VERSION 5.8 ;
BUSBITCHARS "[]" ;
DIVIDERCHAR "/" ;
UNITS
    DATABASE MICRONS 1000 ;
END UNITS

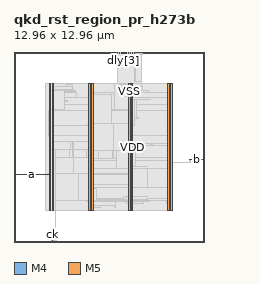
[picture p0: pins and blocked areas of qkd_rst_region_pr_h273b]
MACRO qkd_rst_region_pr_h273b
  FOREIGN qkd_rst_region_pr_h273b 0 0 ;
  CLASS BLOCK ;
  SIZE 12.96 BY 12.96 ;
  PIN a
    DIRECTION INPUT ;
    USE SIGNAL ;
    PORT
      LAYER M4 ;
        RECT  0 4.608 0.084 4.632 ;
    END
    PORT
      LAYER M4 ;
        RECT  0.06 4.608 2.408 4.632 ;
    END
  END a
  PIN b
    DIRECTION OUTPUT ;
    USE SIGNAL ;
    PORT
      LAYER M4 ;
        RECT  12.876 5.616 12.96 5.64 ;
    END
    PORT
      LAYER M4 ;
        RECT  11.977 5.616 12.924 5.64 ;
    END
  END b
  PIN ck
    DIRECTION INPUT ;
    USE SIGNAL ;
    PORT
      LAYER M5 ;
        RECT  2.592 0 2.616 0.084 ;
    END
    PORT
      LAYER M5 ;
        RECT  2.592 0.016 2.616 0.085 ;
    END
  END ck
  PIN dly[0]
    DIRECTION INPUT ;
    USE SIGNAL ;
    PORT
      LAYER M5 ;
        RECT  7.056 12.876 7.08 12.96 ;
    END
  END dly[0]
  PIN dly[1]
    DIRECTION INPUT ;
    USE SIGNAL ;
    PORT
      LAYER M5 ;
        RECT  7.2 12.876 7.224 12.96 ;
    END
  END dly[1]
  PIN dly[2]
    DIRECTION INPUT ;
    USE SIGNAL ;
    PORT
      LAYER M5 ;
        RECT  7.344 12.876 7.368 12.96 ;
    END
  END dly[2]
  PIN dly[3]
    DIRECTION INPUT ;
    USE SIGNAL ;
    PORT
      LAYER M5 ;
        RECT  7.488 12.876 7.512 12.96 ;
    END
  END dly[3]
  PIN dly[4]
    DIRECTION INPUT ;
    USE SIGNAL ;
    PORT
      LAYER M5 ;
        RECT  7.632 12.876 7.656 12.96 ;
    END
  END dly[4]
  PIN dly[5]
    DIRECTION INPUT ;
    USE SIGNAL ;
    PORT
      LAYER M5 ;
        RECT  7.776 12.876 7.8 12.96 ;
    END
  END dly[5]
  PIN dly[6]
    DIRECTION INPUT ;
    USE SIGNAL ;
    PORT
      LAYER M5 ;
        RECT  7.92 12.876 7.944 12.96 ;
    END
  END dly[6]
  PIN dly[7]
    DIRECTION INPUT ;
    USE SIGNAL ;
    PORT
      LAYER M5 ;
        RECT  8.064 12.876 8.088 12.96 ;
    END
  END dly[7]
  PIN por_n
    DIRECTION INPUT ;
    USE SIGNAL ;
    PORT
      LAYER M5 ;
        RECT  8.208 12.876 8.232 12.96 ;
    END
  END por_n
  PIN VDD
    DIRECTION INOUT ;
    USE POWER ;
    PORT
      LAYER M5 ;
        RECT  10.692 2.151 10.812 10.809 ;
        RECT  7.992 2.151 8.112 10.809 ;
        RECT  5.292 2.151 5.412 10.809 ;
        RECT  2.592 2.151 2.712 10.809 ;
    END
  END VDD
  PIN VSS
    DIRECTION INOUT ;
    USE GROUND ;
    PORT
      LAYER M5 ;
        RECT  10.5 2.137 10.62 10.823 ;
        RECT  7.8 2.137 7.92 10.823 ;
        RECT  5.1 2.137 5.22 10.823 ;
        RECT  2.4 2.137 2.52 10.823 ;
    END
  END VSS
  # OT_OBS_CLOSED layer=M5 d_um=1.536 added=5
  OBS
    LAYER RVTN ;
     RECT  2.16 2.16 10.8 2.295 ;
     RECT  2.16 2.565 10.8 2.835 ;
     RECT  2.16 3.105 10.8 3.375 ;
     RECT  2.16 3.645 10.8 3.915 ;
     RECT  2.16 4.185 10.8 4.455 ;
     RECT  2.16 4.725 10.8 4.995 ;
     RECT  2.16 5.265 10.8 5.535 ;
     RECT  2.16 5.805 10.8 6.075 ;
     RECT  2.16 6.345 10.8 6.615 ;
     RECT  2.16 6.885 10.8 7.155 ;
     RECT  2.16 7.425 10.8 7.695 ;
     RECT  2.16 7.965 10.8 8.235 ;
     RECT  2.16 8.505 10.8 8.775 ;
     RECT  2.16 9.045 10.8 9.315 ;
     RECT  2.16 9.585 10.8 9.855 ;
     RECT  2.16 10.125 10.8 10.395 ;
     RECT  2.16 10.665 10.8 10.8 ;
    LAYER RVTP ;
     RECT  2.16 2.295 10.8 2.565 ;
     RECT  2.16 2.835 10.8 3.105 ;
     RECT  2.16 3.375 10.8 3.645 ;
     RECT  2.16 3.915 10.8 4.185 ;
     RECT  2.16 4.455 10.8 4.725 ;
     RECT  2.16 4.995 10.8 5.265 ;
     RECT  2.16 5.535 10.8 5.805 ;
     RECT  2.16 6.075 10.8 6.345 ;
     RECT  2.16 6.615 10.8 6.885 ;
     RECT  2.16 7.155 10.8 7.425 ;
     RECT  2.16 7.695 10.8 7.965 ;
     RECT  2.16 8.235 10.8 8.505 ;
     RECT  2.16 8.775 10.8 9.045 ;
     RECT  2.16 9.315 10.8 9.585 ;
     RECT  2.16 9.855 10.8 10.125 ;
     RECT  2.16 10.395 10.8 10.665 ;
    LAYER M1 ;
     RECT  2.16 2.151 10.8 10.809 ;
    LAYER M2 ;
     RECT  2.16 2.151 10.8 10.809 ;
     RECT  10.8 2.421 10.812 10.539 ;
     RECT  10.812 5.436 12.011 5.454 ;
    LAYER M3 ;
     RECT  5.115 2.143 5.205 2.371 ;
     RECT  2.415 2.143 2.505 2.413 ;
     RECT  7.815 2.143 7.905 2.413 ;
     RECT  10.515 2.143 10.605 2.413 ;
     RECT  5.115 2.371 5.922 2.497 ;
     RECT  6.876 2.371 6.894 2.497 ;
     RECT  7.815 2.413 8.097 2.605 ;
     RECT  7.704 2.605 8.154 2.641 ;
     RECT  10.515 2.413 10.797 2.641 ;
     RECT  5.115 2.497 6.894 2.731 ;
     RECT  7.704 2.641 8.838 2.731 ;
     RECT  4.932 2.731 9.27 2.827 ;
     RECT  4.356 2.827 9.27 2.839 ;
     RECT  10.368 2.641 10.797 2.839 ;
     RECT  4.356 2.839 10.797 2.939 ;
     RECT  4.572 2.939 10.797 3.713 ;
     RECT  3.744 3.721 3.762 3.931 ;
     RECT  3.6 3.931 3.762 3.955 ;
     RECT  4.572 3.713 8.097 3.955 ;
     RECT  2.415 2.413 2.697 4.603 ;
     RECT  2.304 4.603 2.697 4.621 ;
     RECT  3.6 3.955 8.097 4.621 ;
     RECT  2.304 4.621 8.097 4.685 ;
     RECT  2.415 4.685 8.097 5.035 ;
     RECT  9.108 3.713 10.797 5.035 ;
     RECT  2.415 5.035 10.797 5.567 ;
     RECT  11.988 5.431 12.006 5.645 ;
     RECT  2.415 5.567 4.05 5.765 ;
     RECT  4.824 5.567 10.797 5.765 ;
     RECT  2.415 5.765 3.798 6.619 ;
     RECT  2.415 6.619 4.05 6.691 ;
     RECT  4.932 5.765 10.797 6.691 ;
     RECT  2.415 6.691 10.797 7.231 ;
     RECT  2.376 7.231 10.797 8.969 ;
     RECT  2.415 8.969 10.797 9.347 ;
     RECT  3.42 9.347 10.797 9.887 ;
     RECT  5.115 9.887 10.797 10.193 ;
     RECT  3.42 9.887 4.23 10.229 ;
     RECT  5.115 10.193 6.102 10.229 ;
     RECT  6.84 10.193 10.797 10.229 ;
     RECT  2.415 9.347 2.697 10.267 ;
     RECT  3.42 10.229 4.194 10.267 ;
     RECT  2.415 10.267 4.194 10.319 ;
     RECT  6.84 10.229 9.198 10.319 ;
     RECT  2.415 10.319 4.086 10.391 ;
     RECT  5.115 10.229 5.397 10.547 ;
     RECT  10.515 10.229 10.797 10.547 ;
     RECT  2.415 10.391 3.978 10.589 ;
     RECT  6.84 10.319 8.766 10.589 ;
     RECT  3.564 10.589 3.978 10.769 ;
     RECT  6.84 10.589 8.73 10.781 ;
     RECT  2.415 10.589 2.505 10.817 ;
     RECT  5.115 10.547 5.205 10.817 ;
     RECT  7.815 10.781 8.73 10.817 ;
     RECT  10.515 10.547 10.605 10.817 ;
     RECT  6.84 10.781 6.858 10.829 ;
     RECT  8.028 10.817 8.73 10.829 ;
     RECT  8.064 10.829 8.73 10.925 ;
     RECT  8.28 10.925 8.73 12.797 ;
     RECT  8.712 12.797 8.73 12.845 ;
    LAYER M4 ;
     RECT  2.365 7.92 2.408 7.944 ;
     RECT  2.408 2.148 2.512 10.812 ;
     RECT  2.512 2.418 2.704 10.542 ;
     RECT  2.581 0.096 2.867 0.12 ;
     RECT  2.704 9.072 3.443 10.296 ;
     RECT  3.443 9.6 3.665 9.624 ;
     RECT  2.704 6.288 3.881 6.888 ;
     RECT  3.881 6.288 3.98 6.84 ;
     RECT  3.98 5.712 4.067 6.84 ;
     RECT  2.704 7.92 5.029 7.944 ;
     RECT  4.319 2.832 5.101 2.856 ;
     RECT  5.101 2.832 5.108 2.904 ;
     RECT  2.704 3.936 5.108 4.68 ;
     RECT  4.067 6.288 5.108 6.84 ;
     RECT  5.029 7.92 5.108 8.04 ;
     RECT  5.108 2.148 5.212 10.812 ;
     RECT  5.212 2.418 5.404 10.542 ;
     RECT  5.404 2.832 5.609 3.624 ;
     RECT  5.404 5.664 5.753 6.312 ;
     RECT  5.404 7.344 6.617 10.056 ;
     RECT  5.753 5.664 6.716 6.264 ;
     RECT  6.617 7.344 6.716 8.04 ;
     RECT  6.716 5.664 6.803 8.04 ;
     RECT  6.617 9.072 6.829 10.056 ;
     RECT  6.803 5.664 7.009 7.992 ;
     RECT  5.609 2.88 7.477 2.904 ;
     RECT  7.477 2.88 7.657 3.096 ;
     RECT  7.657 2.832 7.808 3.096 ;
     RECT  7.009 4.992 7.808 7.992 ;
     RECT  6.829 9.072 7.808 10.824 ;
     RECT  7.765 12.816 7.909 12.84 ;
     RECT  7.808 2.148 7.912 10.824 ;
     RECT  7.912 2.418 8.053 10.824 ;
     RECT  8.053 2.418 8.104 10.92 ;
     RECT  8.104 10.8 8.137 10.92 ;
     RECT  8.104 7.968 8.237 9.72 ;
     RECT  8.137 10.8 8.243 10.824 ;
     RECT  8.104 5.136 8.309 6.696 ;
     RECT  7.909 12.768 8.309 12.84 ;
     RECT  8.237 8.448 8.345 9.72 ;
     RECT  8.345 8.448 8.489 8.472 ;
     RECT  8.309 12.816 8.741 12.84 ;
     RECT  8.104 2.88 9.101 3.096 ;
     RECT  9.101 2.88 9.137 2.904 ;
     RECT  8.309 5.136 9.137 5.16 ;
     RECT  8.309 6.576 9.281 6.696 ;
     RECT  8.345 9.696 9.281 9.72 ;
     RECT  9.281 6.576 9.425 6.648 ;
     RECT  9.425 6.576 10.508 6.6 ;
     RECT  10.508 2.148 10.612 10.812 ;
     RECT  10.612 2.418 10.804 10.542 ;
    LAYER M5 ;
     RECT  2.592 0.085 2.856 0.131 ;
     RECT  2.832 0.131 2.856 2.137 ;
     RECT  5.1 2.137 5.22 2.151 ;
     RECT  7.8 2.137 7.92 2.151 ;
     RECT  10.5 2.137 10.62 2.151 ;
     RECT  5.1 2.151 5.412 2.821 ;
     RECT  4.368 2.821 5.412 4.645 ;
     RECT  4.032 4.645 5.412 4.691 ;
     RECT  4.032 4.691 4.056 5.747 ;
     RECT  2.4 2.137 2.856 6.323 ;
     RECT  6.768 6.229 6.792 8.051 ;
     RECT  2.4 6.323 2.712 9.061 ;
     RECT  7.8 2.151 8.112 9.925 ;
     RECT  7.632 9.925 8.112 10.165 ;
     RECT  2.4 9.061 3.432 10.307 ;
     RECT  7.344 10.165 8.112 10.741 ;
     RECT  7.2 10.741 8.112 10.789 ;
     RECT  2.4 10.307 2.712 10.809 ;
     RECT  5.1 4.691 5.412 10.809 ;
     RECT  10.5 2.151 10.812 10.809 ;
     RECT  2.4 10.809 2.52 10.823 ;
     RECT  5.1 10.809 5.22 10.823 ;
     RECT  10.5 10.809 10.62 10.823 ;
     RECT  7.056 10.789 8.232 12.876 ;
     RECT  7.08 12.876 7.2 12.944 ;
     RECT  7.224 12.876 7.344 12.944 ;
     RECT  7.368 12.876 7.488 12.944 ;
     RECT  7.512 12.876 7.632 12.944 ;
     RECT  7.656 12.876 7.776 12.944 ;
     RECT  7.8 12.876 7.92 12.944 ;
     RECT  7.944 12.876 8.064 12.944 ;
     RECT  8.088 12.876 8.208 12.944 ;
     RECT  2.856 2.821 4.368 4.645 ;
     RECT  2.856 4.645 4.032 5.747 ;
     RECT  4.056 4.691 5.1 5.747 ;
     RECT  5.412 6.229 6.768 8.051 ;
     RECT  6.792 6.229 7.8 8.051 ;
  END
END qkd_rst_region_pr_h273b
END LIBRARY
